VERSION 5.8 ;
BUSBITCHARS "[]" ;
DIVIDERCHAR "/" ;
UNITS
    DATABASE MICRONS 1000 ;
END UNITS

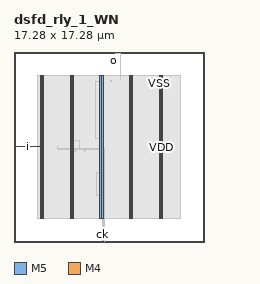
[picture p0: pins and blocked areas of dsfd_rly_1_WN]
MACRO dsfd_rly_1_WN
  FOREIGN dsfd_rly_1_WN 0 0 ;
  CLASS BLOCK ;
  SIZE 17.28 BY 17.28 ;
  PIN ck
    DIRECTION INPUT ;
    USE SIGNAL ;
    PORT
      LAYER M5 ;
        RECT  8.016 0 8.04 0.084 ;
    END
  END ck
  PIN i
    DIRECTION INPUT ;
    USE SIGNAL ;
    PORT
      LAYER M4 ;
        RECT  0 8.688 0.084 8.712 ;
    END
    PORT
      LAYER M4 ;
        RECT  0.06 8.688 2.408 8.712 ;
    END
  END i
  PIN o
    DIRECTION OUTPUT ;
    USE SIGNAL ;
    PORT
      LAYER M5 ;
        RECT  9.072 17.196 9.096 17.28 ;
    END
    PORT
      LAYER M5 ;
        RECT  9.072 17.125 9.096 17.232 ;
    END
  END o
  PIN rs
    DIRECTION INPUT ;
    USE SIGNAL ;
    PORT
      LAYER M5 ;
        RECT  8.112 0 8.136 0.084 ;
    END
  END rs
  PIN VDD
    DIRECTION INOUT ;
    USE POWER ;
    PORT
      LAYER M5 ;
        RECT  13.392 2.151 13.512 15.129 ;
        RECT  10.692 2.151 10.812 15.129 ;
        RECT  7.992 2.151 8.112 15.129 ;
        RECT  5.292 2.151 5.412 15.129 ;
        RECT  2.592 2.151 2.712 15.129 ;
    END
  END VDD
  PIN VSS
    DIRECTION INOUT ;
    USE GROUND ;
    PORT
      LAYER M5 ;
        RECT  13.2 2.137 13.32 15.143 ;
        RECT  10.5 2.137 10.62 15.143 ;
        RECT  7.8 2.137 7.92 15.143 ;
        RECT  5.1 2.137 5.22 15.143 ;
        RECT  2.4 2.137 2.52 15.143 ;
    END
  END VSS
  # OT_OBS_CLOSED layer=M5 d_um=1.536 added=1
  OBS
    LAYER RVTN ;
     RECT  2.16 2.16 15.12 2.295 ;
     RECT  2.16 2.565 15.12 2.835 ;
     RECT  2.16 3.105 15.12 3.375 ;
     RECT  2.16 3.645 15.12 3.915 ;
     RECT  2.16 4.185 15.12 4.455 ;
     RECT  2.16 4.725 15.12 4.995 ;
     RECT  2.16 5.265 15.12 5.535 ;
     RECT  2.16 5.805 15.12 6.075 ;
     RECT  2.16 6.345 15.12 6.615 ;
     RECT  2.16 6.885 15.12 7.155 ;
     RECT  2.16 7.425 15.12 7.695 ;
     RECT  2.16 7.965 15.12 8.235 ;
     RECT  2.16 8.505 15.12 8.775 ;
     RECT  2.16 9.045 15.12 9.315 ;
     RECT  2.16 9.585 15.12 9.855 ;
     RECT  2.16 10.125 15.12 10.395 ;
     RECT  2.16 10.665 15.12 10.935 ;
     RECT  2.16 11.205 15.12 11.475 ;
     RECT  2.16 11.745 15.12 12.015 ;
     RECT  2.16 12.285 15.12 12.555 ;
     RECT  2.16 12.825 15.12 13.095 ;
     RECT  2.16 13.365 15.12 13.635 ;
     RECT  2.16 13.905 15.12 14.175 ;
     RECT  2.16 14.445 15.12 14.715 ;
     RECT  2.16 14.985 15.12 15.12 ;
    LAYER RVTP ;
     RECT  2.16 2.295 15.12 2.565 ;
     RECT  2.16 2.835 15.12 3.105 ;
     RECT  2.16 3.375 15.12 3.645 ;
     RECT  2.16 3.915 15.12 4.185 ;
     RECT  2.16 4.455 15.12 4.725 ;
     RECT  2.16 4.995 15.12 5.265 ;
     RECT  2.16 5.535 15.12 5.805 ;
     RECT  2.16 6.075 15.12 6.345 ;
     RECT  2.16 6.615 15.12 6.885 ;
     RECT  2.16 7.155 15.12 7.425 ;
     RECT  2.16 7.695 15.12 7.965 ;
     RECT  2.16 8.235 15.12 8.505 ;
     RECT  2.16 8.775 15.12 9.045 ;
     RECT  2.16 9.315 15.12 9.585 ;
     RECT  2.16 9.855 15.12 10.125 ;
     RECT  2.16 10.395 15.12 10.665 ;
     RECT  2.16 10.935 15.12 11.205 ;
     RECT  2.16 11.475 15.12 11.745 ;
     RECT  2.16 12.015 15.12 12.285 ;
     RECT  2.16 12.555 15.12 12.825 ;
     RECT  2.16 13.095 15.12 13.365 ;
     RECT  2.16 13.635 15.12 13.905 ;
     RECT  2.16 14.175 15.12 14.445 ;
     RECT  2.16 14.715 15.12 14.985 ;
    LAYER M1 ;
     RECT  2.16 2.151 15.12 15.129 ;
    LAYER M2 ;
     RECT  2.16 2.151 15.12 15.129 ;
    LAYER M3 ;
     RECT  8.028 0.571 8.046 2.143 ;
     RECT  7.815 2.143 8.046 2.191 ;
     RECT  2.415 2.143 2.505 2.413 ;
     RECT  5.115 2.143 5.205 2.413 ;
     RECT  10.515 2.143 10.605 2.413 ;
     RECT  13.215 2.143 13.305 2.413 ;
     RECT  7.815 2.191 8.154 4.145 ;
     RECT  7.815 4.145 8.097 4.261 ;
     RECT  7.524 4.261 8.097 6.305 ;
     RECT  7.74 6.305 8.097 8.195 ;
     RECT  5.115 2.413 5.397 8.239 ;
     RECT  6.48 8.239 6.498 8.311 ;
     RECT  5.115 8.239 5.598 8.401 ;
     RECT  6.336 8.311 6.498 8.429 ;
     RECT  4.644 8.401 5.598 8.437 ;
     RECT  6.336 8.429 6.354 8.465 ;
     RECT  3.96 8.437 5.598 8.473 ;
     RECT  3.96 8.473 5.958 8.477 ;
     RECT  2.415 2.413 2.697 8.683 ;
     RECT  3.96 8.477 3.978 8.699 ;
     RECT  2.304 8.683 2.697 8.735 ;
     RECT  5.115 8.477 5.958 9.239 ;
     RECT  7.815 8.195 8.097 9.391 ;
     RECT  7.452 9.391 8.097 14.639 ;
     RECT  8.82 14.611 8.838 14.711 ;
     RECT  2.415 8.735 2.697 14.867 ;
     RECT  5.115 9.239 5.397 14.867 ;
     RECT  7.815 14.639 8.097 14.867 ;
     RECT  10.515 2.413 10.797 14.867 ;
     RECT  13.215 2.413 13.497 14.867 ;
     RECT  2.415 14.867 2.505 15.137 ;
     RECT  5.115 14.867 5.205 15.137 ;
     RECT  7.815 14.867 7.905 15.137 ;
     RECT  10.515 14.867 10.605 15.137 ;
     RECT  13.215 14.867 13.305 15.137 ;
     RECT  9.648 14.791 9.666 17.165 ;
    LAYER M4 ;
     RECT  2.408 2.148 2.512 15.132 ;
     RECT  2.512 2.418 2.704 14.862 ;
     RECT  4.633 8.448 5.108 8.472 ;
     RECT  5.108 2.148 5.212 15.132 ;
     RECT  5.212 2.418 5.404 14.862 ;
     RECT  5.404 8.448 7.808 8.472 ;
     RECT  7.808 2.148 7.912 15.132 ;
     RECT  8.005 0.096 8.017 0.12 ;
     RECT  7.912 2.418 8.104 14.862 ;
     RECT  8.017 0.096 8.147 0.6 ;
     RECT  8.147 0.096 8.243 0.12 ;
     RECT  8.104 8.448 8.243 8.472 ;
     RECT  9.061 17.136 9.677 17.16 ;
     RECT  10.508 2.148 10.612 15.132 ;
     RECT  10.612 2.418 10.804 14.862 ;
     RECT  13.208 2.148 13.312 15.132 ;
     RECT  13.312 2.418 13.504 14.862 ;
    LAYER M5 ;
     RECT  8.016 0.016 8.136 0.085 ;
     RECT  8.016 0.085 8.232 0.131 ;
     RECT  8.112 0.131 8.232 0.611 ;
     RECT  8.208 0.611 8.232 2.137 ;
     RECT  2.4 2.137 2.52 2.151 ;
     RECT  5.1 2.137 5.22 2.151 ;
     RECT  10.5 2.137 10.62 2.151 ;
     RECT  13.2 2.137 13.32 2.151 ;
     RECT  7.8 2.137 8.232 8.483 ;
     RECT  2.4 2.151 2.712 15.129 ;
     RECT  5.1 2.151 5.412 15.129 ;
     RECT  7.8 8.483 8.112 15.129 ;
     RECT  10.5 2.151 10.812 15.129 ;
     RECT  13.2 2.151 13.512 15.129 ;
     RECT  2.4 15.129 2.52 15.143 ;
     RECT  5.1 15.129 5.22 15.143 ;
     RECT  7.8 15.129 7.92 15.143 ;
     RECT  10.5 15.129 10.62 15.143 ;
     RECT  13.2 15.129 13.32 15.143 ;
     RECT  8.112 0.611 8.208 2.137 ;
  END
END dsfd_rly_1_WN
END LIBRARY
